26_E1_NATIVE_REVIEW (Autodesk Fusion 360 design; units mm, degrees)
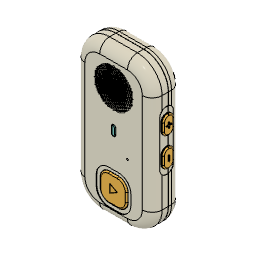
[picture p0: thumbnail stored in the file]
description: Open CASCADE Model
part number: Walkie_One_26_E1_ENGINEERING_REVIEW_ONLY
description: Part Number
part number: MIC_ACOUSTIC_GASKET_INSTALLED_ENVELOPE_part
part number: MIC_ACOUSTIC_GASKET_INSTALLED_ENVELOPE
part number: STATUS_LIGHT_LENS_part
part number: STATUS_LIGHT_LENS
part number: FRONT_ACTION_BUTTON_part
part number: FRONT_ACTION_BUTTON
part number: FRONT_SWITCH_CLAMP_part
part number: FRONT_SWITCH_CLAMP
part number: LED_SERVICE_CLAMP_part
parameter "sourceCaseWidth" = 78
parameter "sourceCaseHeight" = 150
parameter "sourceCaseDepth" = 29.5
parameter "measuredButtonRestGap" = 0.15
parameter "sideTravelTested" = 0.65
parameter "frontTravelTested" = 0.7
parameter "micPortY" = -13.238
parameter "usbPortZ" = -13.2699
base_feature "Base Feature1"
base_feature "Base Feature1"
base_feature "Base Feature1"
base_feature "Base Feature1"
base_feature "Base Feature1"
base_feature "Base Feature1"
base_feature "Base Feature1"
base_feature "Base Feature1"
base_feature "Base Feature1"
base_feature "Base Feature1"
base_feature "Base Feature1"
base_feature "Base Feature1"
base_feature "Base Feature1"
base_feature "Base Feature1"
base_feature "Base Feature1"
base_feature "Base Feature1"
base_feature "Base Feature1"
base_feature "Base Feature1"
base_feature "Base Feature1"
base_feature "Base Feature1"
base_feature "Base Feature1"
base_feature "Base Feature1"
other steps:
create_component "CreateComponent1"
create_component "CreateComponent1"
create_component "CreateComponent1"
create_component "CreateComponent2"
create_component "CreateComponent1"
create_component "CreateComponent3"
create_component "CreateComponent1"
create_component "CreateComponent4"
create_component "CreateComponent1"
create_component "CreateComponent5"
create_component "CreateComponent1"
create_component "CreateComponent6"
create_component "CreateComponent1"
create_component "CreateComponent7"
create_component "CreateComponent1"
create_component "CreateComponent8"
create_component "CreateComponent1"
create_component "CreateComponent9"
create_component "CreateComponent1"
create_component "CreateComponent10"
create_component "CreateComponent1"
create_component "CreateComponent11"
create_component "CreateComponent1"
create_component "CreateComponent12"
create_component "CreateComponent1"
create_component "CreateComponent13"
create_component "CreateComponent1"
create_component "CreateComponent14"
create_component "CreateComponent1"
create_component "CreateComponent15"
create_component "CreateComponent1"
create_component "CreateComponent16"
create_component "CreateComponent1"
create_component "CreateComponent17"
create_component "CreateComponent1"
create_component "CreateComponent18"
create_component "CreateComponent1"
create_component "CreateComponent19"
create_component "CreateComponent1"
create_component "CreateComponent20"
create_component "CreateComponent1"
create_component "CreateComponent21"
create_component "CreateComponent1"
create_component "CreateComponent22"
create_component "CreateComponent1"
